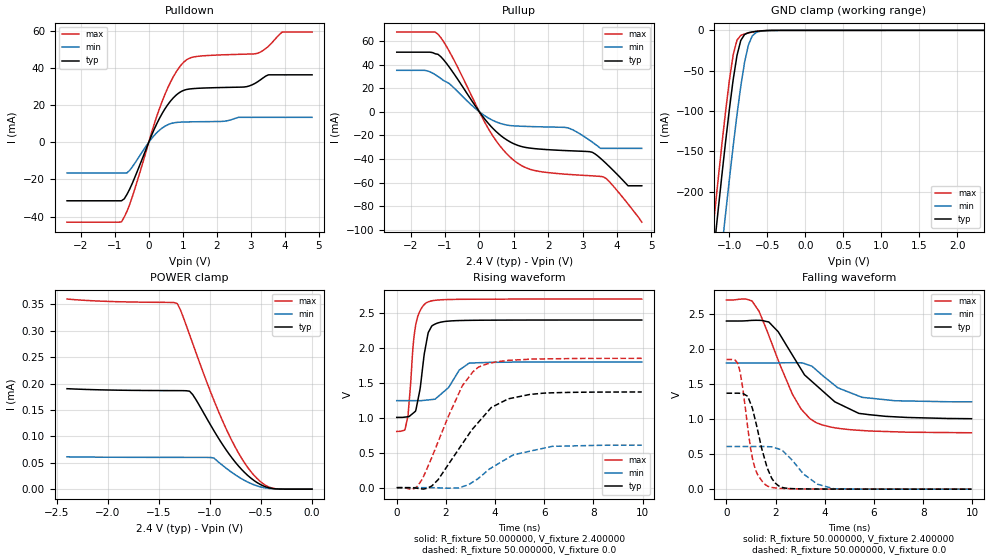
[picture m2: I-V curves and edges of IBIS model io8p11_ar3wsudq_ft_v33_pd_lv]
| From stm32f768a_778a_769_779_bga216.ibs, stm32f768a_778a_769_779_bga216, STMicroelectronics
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|   Model io8p11_ar3wsudq_ft_v33_pd_lv
[Model]  io8p11_ar3wsudq_ft_v33_pd_lv
Model_type I/O
Polarity   Non-Inverting
Enable   Active-Low
Vinl =   0.720000V
Vinh =   1.680000V
Vmeas =  1.200000V
Cref =   30.000000pF
Rref =   100.000000M
Vref =   0.0V
C_comp   3.742400pF   3.690400pF   3.817400pF
[Temperature Range]   25.000000   0.125000k   -40.000000
[Pullup Reference]   2.400000V   1.800000V   2.700000V
[Pulldown Reference]   0.0V   0.0V   0.0V
[POWER Clamp Reference]   2.400000V   1.800000V   2.700000V
[GND Clamp Reference]   0.0V   0.0V   0.0V
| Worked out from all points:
|   slope of the pulldown table from 0 to 0.36 V, typ, clamps not added: 25 ohm
|   slope of the pullup table from 0 to 0.36 V, typ, clamps not added: 27.7 ohm
|   GND clamp passes 1 mA (typ) near -0.62 V on its own axis
|   rising waveform, R_fixture 50.000000, V_fixture 2.400000: 20-80 % time 350ps typ, 712ps min, 273ps max; typ from 1 V to 2.4 V
|   rising waveform, R_fixture 50.000000, V_fixture 0.0: 20-80 % time 1.73ns typ, 1.68ns min, 1.37ns max; typ from 0 V to 1.37 V
|   falling waveform, R_fixture 50.000000, V_fixture 2.400000: 20-80 % time 1.96ns typ, 1.49ns min, 1.39ns max; typ from 2.4 V to 1 V
|   falling waveform, R_fixture 50.000000, V_fixture 0.0: 20-80 % time 598ps typ, 1.04ns min, 459ps max; typ from 1.37 V to 0 V
[Pulldown]
|Voltage   I(typ)   I(min)   I(max)
-2.4V     -31.47mA   -16.45mA   -43.01mA
-800mV    -31.47mA   -16.45mA   -42.85mA
-480mV    -21.98mA   -13.17mA   -29.2mA
80mV      3.63mA     1.966mA    5.014mA
480mV     18.15mA    8.738mA    26.02mA
800mV     25.38mA    10.72mA    37.77mA
1.12V     28.53mA    11.02mA    44.6mA
2.8V      29.84mA    13.49mA    47.53mA
3.2V      32.65mA    13.49mA    48.04mA
3.52V     36.4mA     13.49mA    51.82mA
3.92V     36.4mA     13.49mA    59.44mA
4.8V      36.4mA     13.49mA    59.44mA
[Pullup]
|Voltage   I(typ)   I(min)   I(max)
-2.4V     50.45mA    35.08mA    67.45mA
-1.52V    50.45mA    34.74mA    67.45mA
-1.2V     48.61mA    29.87mA    65.6mA
-800mV    34.81mA    21.95mA    47.28mA
320mV     -11.75mA   -6.207mA   -17.08mA
1.04V     -27.53mA   -11.97mA   -41.91mA
1.6V      -31.13mA   -12.58mA   -49.63mA
2.56V     -32.88mA   -13.52mA   -52.9mA
3.28V     -34.25mA   -25.62mA   -54.18mA
3.6V      -41.44mA   -30.95mA   -55.03mA
4.32V     -62.61mA   -30.95mA   -77.98mA
4.72V     -62.61mA   -30.95mA   -93.4mA
[GND_clamp]
|Voltage   I(typ)   I(min)   I(max)
-2.4V     -1.437A    -1.518A    -1.41A
-1.25V    -315.9mA   -407.2mA   -278.2mA
-1.2V     -270.1mA   -361.3mA   -232.1mA
-1.15V    -225mA     -316mA     -186.8mA
-1.1V     -180.9mA   -271.3mA   -142.7mA
-1.05V    -138.2mA   -227.5mA   -100.5mA
-950mV    -61.14mA   -143.6mA   -30.44mA
-900mV    -31.24mA   -104.7mA   -12.15mA
-850mV    -12.5mA    -69.41mA   -6.236mA
-750mV    -2.91mA    -18.35mA   -3.195mA
-600mV    -761.5uA   -1.227mA   -751.9uA
2.35V     58.09uA    37.93uA    67.25uA
[POWER_clamp]
|Voltage   I(typ)   I(min)   I(max)
-2.4V     190.2uA    61.19uA    359.9uA
-1.32V    186.6uA    60.14uA    351.2uA
-1.29V    186.5uA    60.13uA    339.6uA
-1.2V     185.4uA    60.11uA    292.6uA
-1.17V    179.2uA    60.11uA    276.3uA
-960mV    110.2uA    58.62uA    167.5uA
-870mV    82.44uA    43.99uA    126.3uA
-750mV    50.58uA    26.92uA    78.64uA
-630mV    25.94uA    13.41uA    41.02uA
-510mV    9.22uA     4.527uA    14.97uA
-420mV    2.425uA    1.38uA     3.75uA
0V        0A         0A         0A
[Ramp]
| variable   typ   min   max
dV/dt_r  0.82104/1.72804n   0.36944/1.76414n   1.11072/1.36584n
dV/dt_f  0.83202/1.95959n   0.33240/1.49371n   1.13554/1.39031n
R_load = 50.000000
[Rising Waveform]
R_fixture= 50.000000
V_fixture= 2.400000
V_fixture_min= 1.800000
V_fixture_max= 2.700000
|time   V(typ)   V(min)   V(max)
0s        1.005V     1.245V     804.5mV
320.3ps   1.009V     1.245V     824.1mV
460.5ps   1.015V     1.245V     1.036V
660.7ps   1.064V     1.245V     2.009V
760.8ps   1.093V     1.245V     2.306V
961ps     1.439V     1.245V     2.539V
1.221ns   2.108V     1.253V     2.649V
1.562ns   2.341V     1.266V     2.681V
2.943ns   2.394V     1.781V     2.696V
9.97ns    2.399V     1.799V     2.699V
[Rising Waveform]
R_fixture= 50.000000
V_fixture= 0.0
V_fixture_min= 0.0
V_fixture_max= 0.0
|time   V(typ)   V(min)   V(max)
0s        78.29uV    35.48uV    223.5uV
860.9ps   -10.31mV   60.75uV    27.05mV
1.261ns   -5.229mV   -407.6uV   297.9mV
1.682ns   113.2mV    -2.537mV   655mV
2.663ns   624.6mV    12.36mV    1.454V
3.323ns   935.6mV    133.7mV    1.724V
3.864ns   1.151V     286.5mV    1.787V
5.405ns   1.333V     520.7mV    1.838V
6.326ns   1.357V     591.3mV    1.844V
9.97ns    1.369V     608.5mV    1.85V
[Falling Waveform]
R_fixture= 50.000000
V_fixture= 2.400000
V_fixture_min= 1.800000
V_fixture_max= 2.700000
|time   V(typ)   V(min)   V(max)
0s        2.399V     1.799V     2.699V
1.041ns   2.408V     1.799V     2.684V
1.321ns   2.409V     1.799V     2.54V
1.722ns   2.385V     1.799V     2.194V
2.683ns   1.913V     1.804V     1.355V
3.043ns   1.707V     1.802V     1.141V
3.664ns   1.478V     1.698V     946.3mV
4.525ns   1.227V     1.447V     869.2mV
5.385ns   1.081V     1.328V     840.1mV
9.97ns    1.005V     1.245V     804.5mV
[Falling Waveform]
R_fixture= 50.000000
V_fixture= 0.0
V_fixture_min= 0.0
V_fixture_max= 0.0
|time   V(typ)   V(min)   V(max)
0s        1.369V     608.5mV    1.85V
460.5ps   1.37V      608.4mV    1.794V
660.7ps   1.365V     608.3mV    1.445V
860.9ps   1.326V     608.2mV    893.6mV
1.181ns   973mV      608.1mV    276.5mV
1.662ns   300.2mV    606.4mV    45.36mV
2.262ns   25.69mV    557.4mV    9.738mV
3.143ns   3.643mV    213.8mV    3.238mV
4.364ns   1.366mV    6.242mV    1.176mV
9.97ns    78.29uV    35.48uV    223.5uV
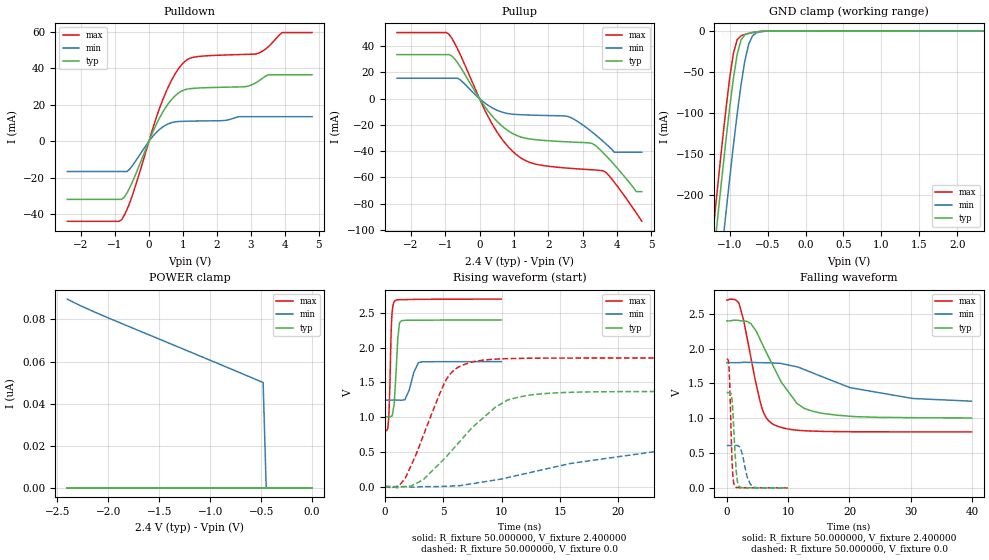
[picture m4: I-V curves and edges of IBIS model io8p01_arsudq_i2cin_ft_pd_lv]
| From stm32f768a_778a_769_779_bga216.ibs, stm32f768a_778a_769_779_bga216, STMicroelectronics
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|   Model io8p01_arsudq_i2cin_ft_pd_lv
[Model]  io8p01_arsudq_i2cin_ft_pd_lv
Model_type I/O
Polarity   Non-Inverting
Enable   Active-Low
Vinl =   0.720000V
Vinh =   1.680000V
Vmeas =  1.200000V
Cref =   50.000000pF
Rref =   100.000000M
Vref =   0.0V
C_comp   2.230300pF   2.174000pF   2.332300pF
[Temperature Range]   25.000000   0.125000k   -40.000000
[Pullup Reference]   2.400000V   1.800000V   2.700000V
[Pulldown Reference]   0.0V   0.0V   0.0V
[POWER Clamp Reference]   2.400000V   1.800000V   2.700000V
[GND Clamp Reference]   0.0V   0.0V   0.0V
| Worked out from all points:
|   slope of the pulldown table from 0 to 0.36 V, typ, clamps not added: 25 ohm
|   slope of the pullup table from 0 to 0.36 V, typ, clamps not added: 27.7 ohm
|   GND clamp passes 1 mA (typ) near -0.62 V on its own axis
|   rising waveform, R_fixture 50.000000, V_fixture 2.400000: 20-80 % time 273ps typ, 605ps min, 184ps max; typ from 1 V to 2.4 V
|   rising waveform, R_fixture 50.000000, V_fixture 0.0: 20-80 % time 4.8ns typ, 12.1ns min, 2.64ns max; typ from 0 V to 1.37 V
|   falling waveform, R_fixture 50.000000, V_fixture 2.400000: 20-80 % time 5.34ns typ, 12.6ns min, 2.67ns max; typ from 2.4 V to 1 V
|   falling waveform, R_fixture 50.000000, V_fixture 0.0: 20-80 % time 524ps typ, 972ps min, 384ps max; typ from 1.37 V to 0 V
[Pulldown]
|Voltage   I(typ)   I(min)   I(max)
-2.4V     -31.73mA   -16.51mA   -43.74mA
-800mV    -31.73mA   -16.51mA   -42.87mA
-480mV    -21.98mA   -13.17mA   -29.2mA
80mV      3.63mA     1.966mA    5.014mA
480mV     18.15mA    8.738mA    26.02mA
800mV     25.38mA    10.72mA    37.77mA
1.12V     28.53mA    11.02mA    44.6mA
2.8V      29.84mA    13.49mA    47.53mA
3.2V      32.65mA    13.49mA    48.04mA
3.52V     36.42mA    13.49mA    51.83mA
3.92V     36.42mA    13.49mA    59.49mA
4.8V      36.42mA    13.49mA    59.49mA
[Pullup]
|Voltage   I(typ)   I(min)   I(max)
-2.4V     33.57mA    15.56mA    50.37mA
-960mV    33.57mA    15.56mA    50.37mA
-560mV    24.29mA    14.3mA     33.54mA
320mV     -11.75mA   -6.207mA   -17.08mA
960mV     -26.47mA   -11.82mA   -40.02mA
1.52V     -30.88mA   -12.51mA   -49.05mA
2.56V     -32.88mA   -13.48mA   -52.9mA
3.28V     -34.19mA   -25.52mA   -54.18mA
3.6V      -41.31mA   -32.62mA   -54.97mA
3.92V     -50.32mA   -40.8mA    -63.63mA
4.56V     -70.8mA    -40.8mA    -87.08mA
4.72V     -70.8mA    -40.8mA    -93.4mA
[GND_clamp]
|Voltage   I(typ)   I(min)   I(max)
-2.4V     -1.424A    -1.508A    -1.393A
-1.25V    -311.2mA   -401.9mA   -273.3mA
-1.2V     -265.4mA   -356.1mA   -227.2mA
-1.15V    -220.4mA   -310.8mA   -181.9mA
-1.1V     -176.3mA   -266.2mA   -137.9mA
-1.05V    -133.8mA   -222.5mA   -95.87mA
-950mV    -57.3mA    -138.9mA   -26.99mA
-900mV    -28.28mA   -100.4mA   -10.6mA
-850mV    -11.02mA   -65.54mA   -5.972mA
-750mV    -2.846mA   -16.51mA   -3.192mA
-600mV    -761.3uA   -1.173mA   -751.9uA
2.35V     58.09uA    37.92uA    67.25uA
[POWER_clamp]
|Voltage   I(typ)   I(min)   I(max)
-2.4V     0A         89.62nA    0A
-2.04V    0A         81.57nA    0A
-480mV    0A         50.01nA    0A
-450mV    0A         0A         0A
0V        0A         0A         0A
[Ramp]
| variable   typ   min   max
dV/dt_r  0.82158/4.79824n   0.38411/12.99045n   1.11042/2.64258n
dV/dt_f  0.83670/5.34237n   0.32364/13.42571n   1.13744/2.67157n
R_load = 50.000000
[Rising Waveform]
R_fixture= 50.000000
V_fixture= 2.400000
V_fixture_min= 1.800000
V_fixture_max= 2.700000
|time   V(typ)   V(min)   V(max)
0s        1.005V     1.245V     804.2mV
240.2ps   1.005V     1.245V     824.9mV
340.3ps   1.005V     1.245V     987.2mV
600.6ps   1.014V     1.246V     2.44V
860.9ps   1.346V     1.246V     2.674V
1.121ns   2.146V     1.245V     2.689V
1.381ns   2.381V     1.244V     2.691V
1.722ns   2.394V     1.251V     2.692V
2.903ns   2.395V     1.785V     2.696V
9.97ns    2.399V     1.799V     2.699V
[Rising Waveform]
R_fixture= 50.000000
V_fixture= 0.0
V_fixture_min= 0.0
V_fixture_max= 0.0
|time   V(typ)   V(min)   V(max)
0s        178.1uV    73.91uV    433.7uV
1.201ns   -14.27mV   132.9uV    8.83mV
1.762ns   -1.061mV   -612.3uV   121.8mV
3.283ns   97.59mV    -600uV     725.8mV
5.125ns   404mV      3.401mV    1.498V
7.287ns   813.5mV    36mV       1.785V
10.49ns   1.244V     127.8mV    1.842V
13.13ns   1.33V      227.8mV    1.849V
24.82ns   1.369V     542.8mV    1.851V
39.88ns   1.369V     608.4mV    1.851V
[Falling Waveform]
R_fixture= 50.000000
V_fixture= 2.400000
V_fixture_min= 1.800000
V_fixture_max= 2.700000
|time   V(typ)   V(min)   V(max)
0s        2.399V     1.799V     2.699V
2.002ns   2.404V     1.8V       2.652V
2.803ns   2.397V     1.804V     2.387V
3.924ns   2.361V     1.803V     1.878V
5.766ns   2.072V     1.798V     1.136V
7.688ns   1.729V     1.794V     907.8mV
11.45ns   1.211V     1.739V     828.9mV
14.01ns   1.101V     1.651V     815.7mV
20.1ns    1.029V     1.44V      806.6mV
39.88ns   1.005V     1.245V     804.2mV
[Falling Waveform]
R_fixture= 50.000000
V_fixture= 0.0
V_fixture_min= 0.0
V_fixture_max= 0.0
|time   V(typ)   V(min)   V(max)
0s        1.369V     608.4mV    1.851V
380.4ps   1.369V     608.4mV    1.717V
480.5ps   1.369V     608.4mV    1.52V
880.9ps   1.253V     608.2mV    364.6mV
1.041ns   1.033V     607.9mV    129.9mV
1.261ns   648.8mV    607.8mV    34.04mV
1.702ns   115.4mV    609.8mV    4.511mV
2.062ns   17.39mV    592.2mV    2.525mV
3.864ns   1.054mV    51mV       1.255mV
9.97ns    178.1uV    73.91uV    433.7uV
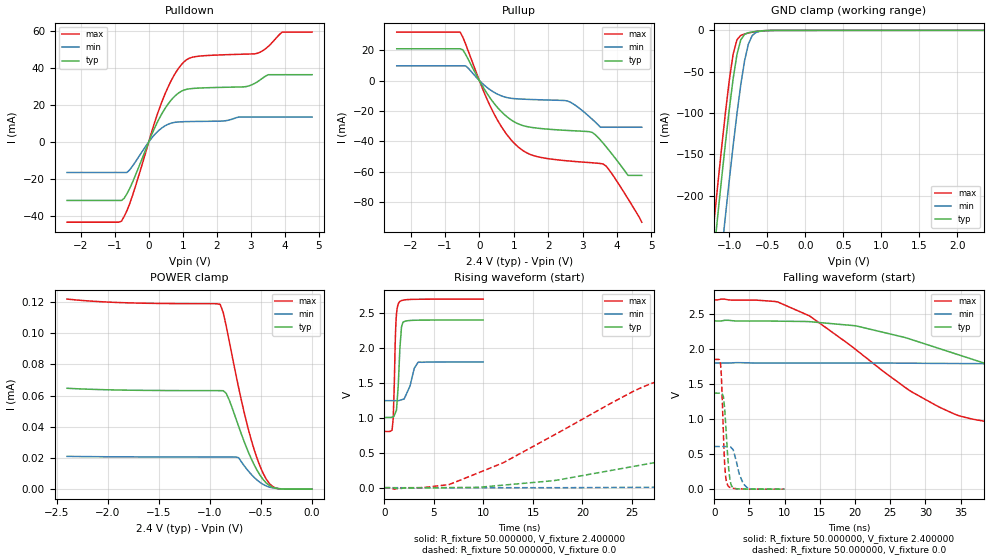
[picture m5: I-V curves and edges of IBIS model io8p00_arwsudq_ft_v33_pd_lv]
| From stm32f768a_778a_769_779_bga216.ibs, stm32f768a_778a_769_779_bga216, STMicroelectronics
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|   Model io8p00_arwsudq_ft_v33_pd_lv
[Model]  io8p00_arwsudq_ft_v33_pd_lv
Model_type I/O
Polarity   Non-Inverting
Enable   Active-Low
Vinl =   0.720000V
Vinh =   1.680000V
Vmeas =  1.200000V
Cref =   50.000000pF
Rref =   100.000000M
Vref =   0.0V
C_comp   2.828400pF   2.771400pF   2.910300pF
[Temperature Range]   25.000000   0.125000k   -40.000000
[Pullup Reference]   2.400000V   1.800000V   2.700000V
[Pulldown Reference]   0.0V   0.0V   0.0V
[POWER Clamp Reference]   2.400000V   1.800000V   2.700000V
[GND Clamp Reference]   0.0V   0.0V   0.0V
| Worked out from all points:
|   slope of the pulldown table from 0 to 0.36 V, typ, clamps not added: 25 ohm
|   slope of the pullup table from 0 to 0.36 V, typ, clamps not added: 27.7 ohm
|   GND clamp passes 1 mA (typ) near -0.62 V on its own axis
|   rising waveform, R_fixture 50.000000, V_fixture 2.400000: 20-80 % time 322ps typ, 710ps min, 219ps max; typ from 1 V to 2.4 V
|   rising waveform, R_fixture 50.000000, V_fixture 0.0: 20-80 % time 30.9ns typ, 81.7ns min, 14.6ns max; typ from 0 V to 1.37 V
|   falling waveform, R_fixture 50.000000, V_fixture 2.400000: 20-80 % time 28.7ns typ, 81.5ns min, 16.1ns max; typ from 2.4 V to 1 V
|   falling waveform, R_fixture 50.000000, V_fixture 0.0: 20-80 % time 551ps typ, 1.05ns min, 407ps max; typ from 1.37 V to 0 V
[Pulldown]
|Voltage   I(typ)   I(min)   I(max)
-2.4V     -31.66mA   -16.51mA   -43.43mA
-800mV    -31.66mA   -16.51mA   -42.86mA
-480mV    -21.98mA   -13.17mA   -29.2mA
80mV      3.63mA     1.966mA    5.014mA
480mV     18.15mA    8.738mA    26.02mA
800mV     25.38mA    10.72mA    37.77mA
1.12V     28.53mA    11.02mA    44.6mA
2.8V      29.84mA    13.48mA    47.53mA
3.2V      32.65mA    13.48mA    48.04mA
3.52V     36.42mA    13.48mA    51.83mA
3.92V     36.42mA    13.48mA    59.48mA
4.8V      36.42mA    13.48mA    59.48mA
[Pullup]
|Voltage   I(typ)   I(min)   I(max)
-2.4V     20.89mA    9.66mA     31.89mA
-560mV    20.89mA    9.66mA     31.89mA
-400mV    17.28mA    9.66mA     24.06mA
320mV     -11.75mA   -6.207mA   -17.08mA
640mV     -20.52mA   -10.1mA    -30.35mA
960mV     -26.47mA   -11.82mA   -40.02mA
1.52V     -30.88mA   -12.51mA   -49.05mA
2.56V     -32.88mA   -13.49mA   -52.9mA
3.28V     -34.2mA    -25.51mA   -54.18mA
3.6V      -41.34mA   -30.77mA   -55mA
4.32V     -62.5mA    -30.77mA   -77.89mA
4.72V     -62.5mA    -30.77mA   -93.3mA
[GND_clamp]
|Voltage   I(typ)   I(min)   I(max)
-2.4V     -1.428A    -1.51A     -1.401A
-1.2V     -266.4mA   -356.3mA   -229.4mA
-1.15V    -221.3mA   -311mA     -184.1mA
-1.1V     -177.3mA   -266.4mA   -140mA
-1.05V    -134.8mA   -222.7mA   -97.98mA
-950mV    -58.22mA   -139.2mA   -28.55mA
-900mV    -29.04mA   -100.6mA   -11.28mA
-850mV    -11.42mA   -65.77mA   -6.081mA
-750mV    -2.864mA   -16.63mA   -3.193mA
-700mV    -1.925mA   -6.327mA   -2.195mA
-600mV    -761.3uA   -1.176mA   -751.9uA
2.35V     58.09uA    37.92uA    67.25uA
[POWER_clamp]
|Voltage   I(typ)   I(min)   I(max)
-2.4V     64.71uA    21.03uA    121.9uA
-1.86V    63.55uA    20.74uA    119.6uA
-900mV    63.18uA    20.63uA    118.5uA
-870mV    63.14uA    20.63uA    113.2uA
-840mV    61.36uA    20.62uA    104.3uA
-720mV    40.37uA    20.18uA    65.28uA
-630mV    24.69uA    12.08uA    39.85uA
-540mV    12.26uA    5.907uA    20uA
-480mV    6.236uA    3.061uA    10.23uA
-420mV    2.4uA      1.365uA    3.726uA
-360mV    667.9nA    564nA      839.6nA
0V        0A         0A         0A
[Ramp]
| variable   typ   min   max
dV/dt_r  0.82158/30.91104n   0.36271/83.77680n   1.11054/14.60240n
dV/dt_f  0.83664/28.69719n   0.32706/81.70446n   1.13680/16.06318n
R_load = 50.000000
[Rising Waveform]
R_fixture= 50.000000
V_fixture= 2.400000
V_fixture_min= 1.800000
V_fixture_max= 2.700000
|time   V(typ)   V(min)   V(max)
0s        1.005V     1.245V     804.1mV
780.8ps   1.011V     1.245V     844mV
880.9ps   1.015V     1.245V     986.6mV
1.161ns   1.091V     1.245V     2.379V
1.381ns   1.445V     1.245V     2.624V
1.481ns   1.756V     1.248V     2.654V
1.722ns   2.301V     1.258V     2.676V
1.882ns   2.369V     1.265V     2.683V
3.403ns   2.397V     1.796V     2.696V
9.97ns    2.399V     1.799V     2.699V
[Rising Waveform]
R_fixture= 50.000000
V_fixture= 0.0
V_fixture_min= 0.0
V_fixture_max= 0.0
|time   V(typ)   V(min)   V(max)
0s        8.172nV    277.6nV    27.6nV
7.007ns   1.534mV    -64.06uV   71.3mV
17.02ns   99.48mV    85.71uV    745.3mV
28.53ns   390.5mV    6.94mV     1.565V
35.54ns   586.7mV    17.4mV     1.729V
44.04ns   832.1mV    46.3mV     1.798V
61.06ns   1.19V      104.1mV    1.84V
85.09ns   1.329V     220.6mV    1.848V
153.2ns   1.367V     509.8mV    1.851V
249.2ns   1.369V     608.5mV    1.851V
[Falling Waveform]
R_fixture= 50.000000
V_fixture= 2.400000
V_fixture_min= 1.800000
V_fixture_max= 2.700000
|time   V(typ)   V(min)   V(max)
0s        2.399V     1.799V     2.699V
9.009ns   2.396V     1.798V     2.67V
13.51ns   2.389V     1.798V     2.472V
20.02ns   2.33V      1.798V     1.997V
32.03ns   2.003V     1.793V     1.167V
45.05ns   1.577V     1.77V      901.7mV
62.06ns   1.217V     1.707V     843.8mV
85.09ns   1.077V     1.579V     818.2mV
157.2ns   1.012V     1.324V     804.9mV
249.2ns   1.005V     1.245V     804.1mV
[Falling Waveform]
R_fixture= 50.000000
V_fixture= 0.0
V_fixture_min= 0.0
V_fixture_max= 0.0
|time   V(typ)   V(min)   V(max)
0s        1.369V     608.5mV    1.851V
900.9ps   1.37V      608.3mV    1.791V
1.081ns   1.366V     608.2mV    1.462V
1.481ns   1.154V     607.9mV    367.9mV
1.922ns   469.3mV    609.1mV    55.96mV
2.262ns   119.6mV    606.1mV    24.15mV
2.723ns   18.74mV    551.1mV    11.47mV
3.584ns   3.171mV    208.2mV    4.054mV
4.805ns   948uV      9.338mV    1.209mV
9.97ns    8.172nV    277.6nV    27.6nV
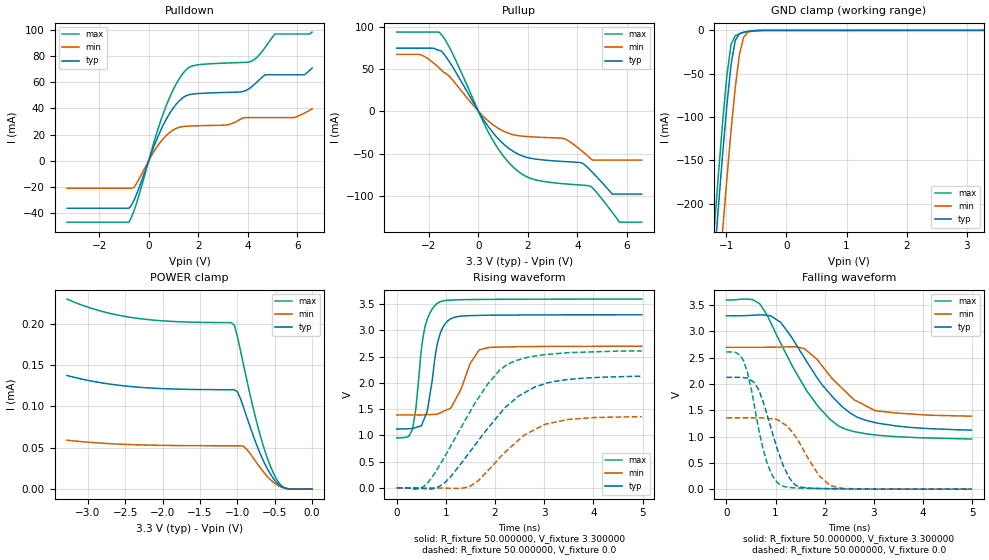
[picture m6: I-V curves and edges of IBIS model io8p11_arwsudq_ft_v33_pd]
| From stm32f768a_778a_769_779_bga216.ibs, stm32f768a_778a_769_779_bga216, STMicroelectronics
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|   Model io8p11_arwsudq_ft_v33_pd
[Model]  io8p11_arwsudq_ft_v33_pd
Model_type I/O
Polarity   Non-Inverting
Enable   Active-Low
Vinl =   0.990000V
Vinh =   2.310000V
Vmeas =  1.650000V
Cref =   30.000000pF
Rref =   100.000000M
Vref =   0.0V
C_comp   2.911600pF   2.826600pF   2.984500pF
[Temperature Range]   25.000000   0.125000k   -40.000000
[Pullup Reference]   3.300000V   2.700000V   3.600000V
[Pulldown Reference]   0.0V   0.0V   0.0V
[POWER Clamp Reference]   3.300000V   2.700000V   3.600000V
[GND Clamp Reference]   0.0V   0.0V   0.0V
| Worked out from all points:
|   slope of the pulldown table from 0 to 0.495 V, typ, clamps not added: 20.9 ohm
|   slope of the pullup table from 0 to 0.495 V, typ, clamps not added: 22.6 ohm
|   GND clamp passes 1 mA (typ) near -0.62 V on its own axis
|   rising waveform, R_fixture 50.000000, V_fixture 3.300000: 20-80 % time 222ps typ, 364ps min, 191ps max; typ from 1.12 V to 3.3 V
|   rising waveform, R_fixture 50.000000, V_fixture 0.0: 20-80 % time 1.14ns typ, 961ps min, 1.02ns max; typ from 0 V to 2.13 V
|   falling waveform, R_fixture 50.000000, V_fixture 3.300000: 20-80 % time 1.02ns typ, 830ps min, 1ns max; typ from 3.3 V to 1.12 V
|   falling waveform, R_fixture 50.000000, V_fixture 0.0: 20-80 % time 437ps typ, 538ps min, 360ps max; typ from 2.13 V to 0 V
[Pulldown]
|Voltage   I(typ)   I(min)   I(max)
-3.3V     -36.38mA   -21.07mA   -47.08mA
-800mV    -36.38mA   -21.07mA   -47.08mA
-600mV    -30.5mA    -20.54mA   -38.69mA
700mV     31.4mA     19.11mA    41.71mA
1.2V      45.15mA    25.37mA    61.75mA
1.6V      50.35mA    26.5mA     71.06mA
3.1V      52.27mA    27.26mA    74.75mA
4.1V      55.7mA     33.02mA    75.8mA
4.7V      65.79mA    33.02mA    86.63mA
5.1V      65.79mA    33.02mA    97.02mA
6.3V      65.87mA    36.5mA     97.02mA
6.6V      70.92mA    39.71mA    98.48mA
[Pullup]
|Voltage   I(typ)   I(min)   I(max)
-3.3V     74.74mA    67.41mA    93.78mA
-2.3V     74.74mA    66.57mA    93.78mA
-1.5V     71.46mA    49mA       91.15mA
500mV     -22.07mA   -14mA      -30.03mA
1.6V      -50.64mA   -28.81mA   -70.96mA
2.3V      -56.49mA   -30.49mA   -81.16mA
3.5V      -59.53mA   -32.66mA   -85.92mA
4.2V      -61.45mA   -47.47mA   -87.46mA
4.5V      -69.1mA    -55.02mA   -88.4mA
5.4V      -98mA      -57.7mA    -119.3mA
5.7V      -98mA      -57.7mA    -131.3mA
6.6V      -98mA      -57.7mA    -131.3mA
[GND_clamp]
|Voltage   I(typ)   I(min)   I(max)
-3.3V     -2.32A     -2.397A    -2.296A
-1.2V     -266.4mA   -356.3mA   -229.4mA
-1.13V    -203.6mA   -293.1mA   -166.3mA
-1.06V    -143.2mA   -231.4mA   -106.2mA
-990mV    -86.95mA   -171.8mA   -52.65mA
-920mV    -39.66mA   -115.8mA   -16.37mA
-850mV    -11.5mA    -65.84mA   -6.125mA
-780mV    -3.846mA   -27.59mA   -3.894mA
-710mV    -2.102mA   -7.761mA   -2.396mA
-640mV    -1.159mA   -2.138mA   -1.234mA
-570mV    -535.1uA   -809uA     -490.2uA
3.28V     81.28uA    57.87uA    93.98uA
[POWER_clamp]
|Voltage   I(typ)   I(min)   I(max)
-3.28V    137.3uA    59.14uA    229.6uA
-2.36V    123.4uA    53.65uA    206.6uA
-1.08V    120.1uA    52.41uA    201.1uA
-1.04V    120uA      52.41uA    198uA
-1V       117.7uA    52.4uA     184.5uA
-920mV    99.46uA    51.91uA    151.2uA
-720mV    48.42uA    29.12uA    73.51uA
-600mV    24.82uA    15.47uA    37.72uA
-520mV    13.1uA     8.45uA     19.84uA
-440mV    5.058uA    3.61uA     7.276uA
-360mV    1.193uA    1.129uA    1.311uA
0V        0A         0A         0A
[Ramp]
| variable   typ   min   max
dV/dt_r  1.26546/1.13882n   0.80862/0.95608n   1.56156/1.02292n
dV/dt_f  1.28214/1.01194n   0.77616/0.82055n   1.57188/1.00030n
R_load = 50.000000
[Rising Waveform]
R_fixture= 50.000000
V_fixture= 3.300000
V_fixture_min= 2.700000
V_fixture_max= 3.600000
|time   V(typ)   V(min)   V(max)
0s        1.123V     1.391V     953.8mV
320.3ps   1.132V     1.39V      1.116V
390.4ps   1.152V     1.39V      1.523V
500.5ps   1.184V     1.39V      2.633V
620.6ps   1.46V      1.395V     3.212V
850.9ps   2.834V     1.417V     3.532V
1.101ns   3.223V     1.522V     3.578V
1.491ns   3.282V     2.367V     3.589V
1.682ns   3.287V     2.63V      3.591V
4.985ns   3.299V     2.699V     3.598V
[Rising Waveform]
R_fixture= 50.000000
V_fixture= 0.0
V_fixture_min= 0.0
V_fixture_max= 0.0
|time   V(typ)   V(min)   V(max)
0s        214.8uV    83.29uV    610.9uV
550.6ps   -11.26mV   -120.3uV   29.4mV
951ps     78.66mV    -4.051mV   559.2mV
1.481ns   679.7mV    25.48mV    1.437V
1.852ns   1.134V     325.4mV    1.98V
2.232ns   1.553V     707.1mV    2.34V
2.593ns   1.811V     1.006V     2.472V
3.023ns   1.988V     1.215V     2.54V
3.493ns   2.066V     1.306V     2.577V
4.985ns   2.127V     1.358V     2.61V
[Falling Waveform]
R_fixture= 50.000000
V_fixture= 3.300000
V_fixture_min= 2.700000
V_fixture_max= 3.600000
|time   V(typ)   V(min)   V(max)
0s        3.299V     2.699V     3.598V
530.5ps   3.309V     2.699V     3.607V
670.7ps   3.314V     2.699V     3.531V
1.101ns   3.175V     2.704V     2.78V
1.582ns   2.505V     2.676V     1.954V
1.862ns   2.093V     2.445V     1.577V
2.292ns   1.628V     1.975V     1.196V
2.663ns   1.368V     1.67V      1.083V
3.033ns   1.265V     1.491V     1.031V
4.985ns   1.123V     1.391V     953.8mV
[Falling Waveform]
R_fixture= 50.000000
V_fixture= 0.0
V_fixture_min= 0.0
V_fixture_max= 0.0
|time   V(typ)   V(min)   V(max)
0s        2.127V     1.358V     2.61V
350.4ps   2.122V     1.357V     2.439V
560.6ps   2.029V     1.357V     1.623V
670.7ps   1.861V     1.356V     1.073V
830.8ps   1.403V     1.348V     487.9mV
1.101ns   589.4mV    1.283V     79.49mV
1.401ns   80.19mV    1.006V     25.35mV
1.882ns   12.81mV    260mV      12.34mV
2.102ns   9.137mV    76.17mV    9.665mV
4.985ns   214.8uV    83.29uV    610.9uV
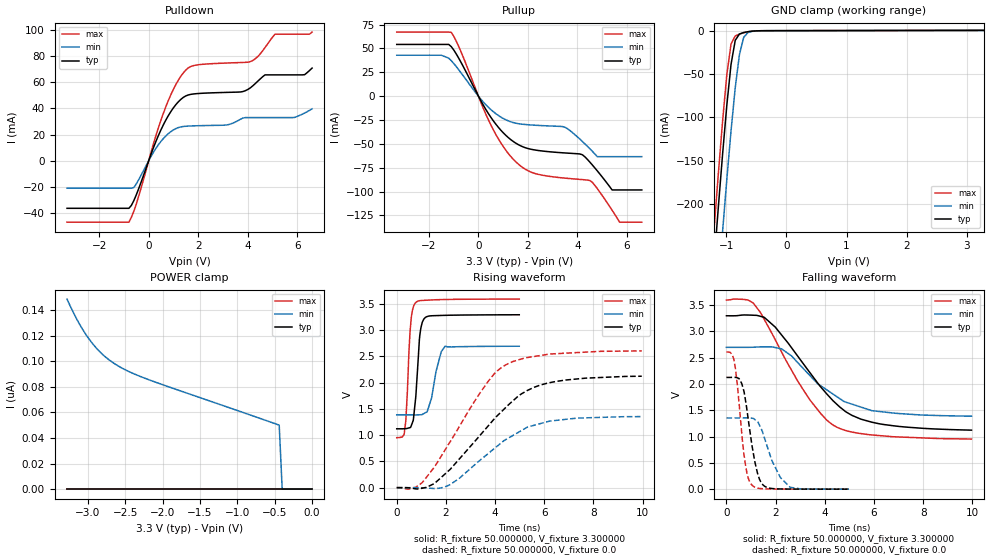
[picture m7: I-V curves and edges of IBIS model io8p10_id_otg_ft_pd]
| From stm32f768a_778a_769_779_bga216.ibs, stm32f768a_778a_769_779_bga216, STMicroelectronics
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|   Model io8p10_id_otg_ft_pd
[Model]  io8p10_id_otg_ft_pd
Model_type I/O
Polarity   Non-Inverting
Enable   Active-Low
Vinl =   0.990000V
Vinh =   2.310000V
Vmeas =  1.650000V
Cref =   40.000000pF
Rref =   100.000000M
Vref =   0.0V
C_comp   2.283100pF   2.214500pF   2.357400pF
[Temperature Range]   25.000000   0.125000k   -40.000000
[Pullup Reference]   3.300000V   2.700000V   3.600000V
[Pulldown Reference]   0.0V   0.0V   0.0V
[POWER Clamp Reference]   3.300000V   2.700000V   3.600000V
[GND Clamp Reference]   0.0V   0.0V   0.0V
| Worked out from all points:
|   slope of the pulldown table from 0 to 0.495 V, typ, clamps not added: 20.9 ohm
|   slope of the pullup table from 0 to 0.495 V, typ, clamps not added: 22.6 ohm
|   GND clamp passes 1 mA (typ) near -0.62 V on its own axis
|   rising waveform, R_fixture 50.000000, V_fixture 3.300000: 20-80 % time 194ps typ, 347ps min, 166ps max; typ from 1.12 V to 3.29 V
|   rising waveform, R_fixture 50.000000, V_fixture 0.0: 20-80 % time 2.52ns typ, 2.28ns min, 2.11ns max; typ from 0 V to 2.12 V
|   falling waveform, R_fixture 50.000000, V_fixture 3.300000: 20-80 % time 2.26ns typ, 2.05ns min, 2.03ns max; typ from 3.29 V to 1.12 V
|   falling waveform, R_fixture 50.000000, V_fixture 0.0: 20-80 % time 432ps typ, 669ps min, 337ps max; typ from 2.12 V to 0 V
[Pulldown]
|Voltage   I(typ)   I(min)   I(max)
-3.3V     -36.46mA   -21.1mA    -47.09mA
-800mV    -36.46mA   -21.1mA    -47.09mA
-600mV    -30.5mA    -20.54mA   -38.68mA
700mV     31.39mA    19.11mA    41.7mA
1.2V      45.14mA    25.37mA    61.74mA
1.6V      50.34mA    26.49mA    71.04mA
3.1V      52.26mA    27.25mA    74.74mA
4.1V      55.69mA    32.98mA    75.78mA
4.7V      65.7mA     32.98mA    86.67mA
5.1V      65.7mA     32.98mA    96.88mA
6.3V      65.85mA    36.49mA    96.88mA
6.6V      70.9mA     39.7mA     98.46mA
[Pullup]
|Voltage   I(typ)   I(min)   I(max)
-3.3V     54.22mA    42.9mA     67.16mA
-1.1V     51.99mA    37.29mA    66.89mA
500mV     -22.06mA   -14mA      -30.03mA
1.5V      -49.1mA    -28.3mA    -68.56mA
2.2V      -56.04mA   -30.32mA   -80.35mA
3.5V      -59.53mA   -32.65mA   -85.92mA
4.2V      -61.43mA   -47.48mA   -87.46mA
4.5V      -69.07mA   -55.13mA   -88.38mA
4.8V      -78.23mA   -63.4mA    -96.83mA
5.4V      -98.3mA    -63.4mA    -119.6mA
5.7V      -98.3mA    -63.4mA    -132.1mA
6.6V      -98.3mA    -63.4mA    -132.1mA
[GND_clamp]
|Voltage   I(typ)   I(min)   I(max)
-3.3V     -2.316A    -2.396A    -2.289A
-1.2V     -265.5mA   -356.1mA   -227.2mA
-1.13V    -202.7mA   -292.9mA   -164.2mA
-1.06V    -142.2mA   -231.2mA   -104.1mA
-990mV    -86mA      -171.6mA   -50.76mA
-920mV    -38.84mA   -115.5mA   -15.35mA
-850mV    -11.15mA   -65.63mA   -6.09mA
-780mV    -3.853mA   -27.45mA   -3.961mA
-710mV    -2.153mA   -7.739mA   -2.46mA
-640mV    -1.209mA   -2.169mA   -1.292mA
-570mV    -580.3uA   -846.3uA   -542.8uA
3.28V     342.5uA    239.2uA    398.5uA
[POWER_clamp]
|Voltage   I(typ)   I(min)   I(max)
-3.28V    0A         148.5nA    0A
-3.2V     0A         138.6nA    0A
-3.12V    0A         129.7nA    0A
-3.04V    0A         122nA      0A
-2.96V    0A         115.3nA    0A
-2.8V     0A         105.1nA    0A
-2.6V     0A         96.44nA    0A
-2.4V     0A         90.52nA    0A
-2.16V    0A         84.97nA    0A
-440mV    0A         50.04nA    0A
-400mV    0A         0A         0A
0V        0A         0A         0A
[Ramp]
| variable   typ   min   max
dV/dt_r  1.26426/2.51289n   0.80916/2.28463n   1.56204/2.11910n
dV/dt_f  1.28196/2.24730n   0.77772/2.03699n   1.57323/2.03479n
R_load = 50.000000
[Rising Waveform]
R_fixture= 50.000000
V_fixture= 3.300000
V_fixture_min= 2.700000
V_fixture_max= 3.600000
|time   V(typ)   V(min)   V(max)
0s        1.121V     1.387V     952.6mV
300.3ps   1.123V     1.387V     1.014V
370.4ps   1.125V     1.387V     1.277V
550.6ps   1.146V     1.387V     3.019V
670.7ps   1.28V      1.386V     3.436V
760.8ps   1.669V     1.386V     3.521V
940.9ps   2.912V     1.389V     3.563V
1.171ns   3.246V     1.429V     3.571V
1.972ns   3.284V     2.696V     3.585V
4.985ns   3.295V     2.695V     3.594V
[Rising Waveform]
R_fixture= 50.000000
V_fixture= 0.0
V_fixture_min= 0.0
V_fixture_max= 0.0
|time   V(typ)   V(min)   V(max)
0s        344.8uV    197.6uV    679.7uV
460.5ps   -2.481mV   133.5uV    -29mV
1.041ns   -10.08mV   -1.937mV   97.3mV
1.542ns   81.92mV    -17.45mV   398.2mV
2.162ns   343.7mV    55.55mV    866.7mV
3.744ns   1.189V     658.5mV    2.041V
4.444ns   1.532V     917.9mV    2.342V
5.305ns   1.85V      1.151V     2.479V
6.166ns   1.995V     1.262V     2.541V
9.97ns    2.124V     1.354V     2.607V
[Falling Waveform]
R_fixture= 50.000000
V_fixture= 3.300000
V_fixture_min= 2.700000
V_fixture_max= 3.600000
|time   V(typ)   V(min)   V(max)
0s        3.295V     2.695V     3.594V
880.9ps   3.309V     2.695V     3.594V
1.101ns   3.305V     2.697V     3.531V
1.542ns   3.263V     2.705V     3.223V
2.242ns   2.931V     2.665V     2.608V
3.383ns   2.222V     2.165V     1.704V
4.384ns   1.66V      1.792V     1.205V
5.105ns   1.402V     1.616V     1.085V
6.206ns   1.243V     1.477V     1.019V
9.97ns    1.121V     1.387V     952.6mV
[Falling Waveform]
R_fixture= 50.000000
V_fixture= 0.0
V_fixture_min= 0.0
V_fixture_max= 0.0
|time   V(typ)   V(min)   V(max)
0s        2.124V     1.354V     2.607V
300.3ps   2.125V     1.354V     2.468V
450.5ps   2.114V     1.354V     1.949V
620.6ps   2.01V      1.354V     1.071V
830.8ps   1.516V     1.356V     312.8mV
1.041ns   823.5mV    1.348V     76.36mV
1.451ns   99.48mV    1.109V     9.633mV
1.852ns   12.75mV    539.9mV    3.701mV
2.583ns   2.074mV    39.7mV     1.691mV
4.985ns   344.8uV    197.6uV    679.7uV
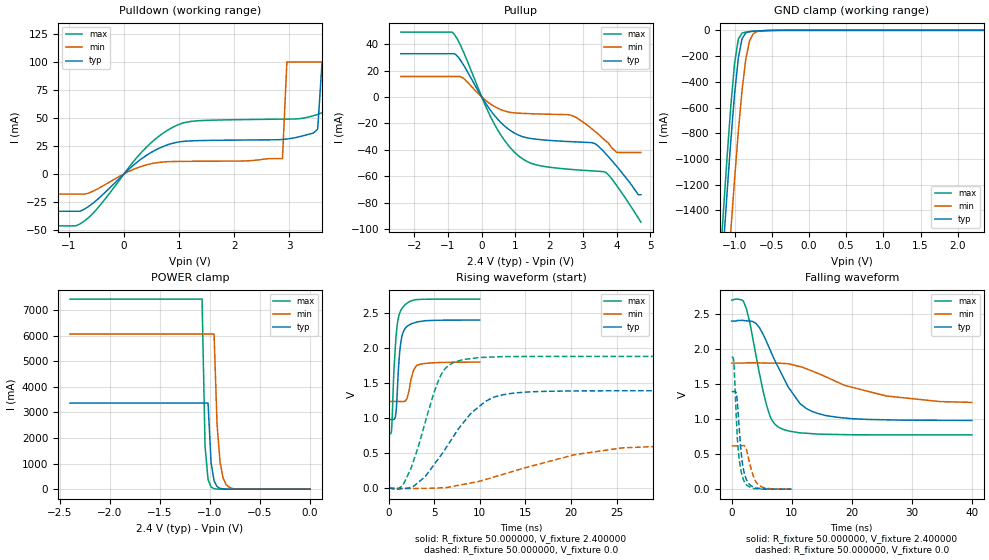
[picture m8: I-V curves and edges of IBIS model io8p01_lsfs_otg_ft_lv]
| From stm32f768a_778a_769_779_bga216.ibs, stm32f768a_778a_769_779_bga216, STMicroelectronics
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|   Model io8p01_lsfs_otg_ft_lv
[Model]  io8p01_lsfs_otg_ft_lv
Model_type I/O
Polarity   Non-Inverting
Enable   Active-Low
Vinl =   0.720000V
Vinh =   1.680000V
Vmeas =  1.200000V
Cref =   50.000000pF
Rref =   100.000000M
Vref =   0.0V
C_comp   7.971100pF   7.737700pF   8.264100pF
[Temperature Range]   25.000000   0.125000k   -40.000000
[Pullup Reference]   2.400000V   1.800000V   2.700000V
[Pulldown Reference]   0.0V   0.0V   0.0V
[POWER Clamp Reference]   2.400000V   1.800000V   2.700000V
[GND Clamp Reference]   0.0V   0.0V   0.0V
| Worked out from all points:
|   slope of the pulldown table from 0 to 0.36 V, typ, clamps not added: 24.1 ohm
|   slope of the pullup table from 0 to 0.36 V, typ, clamps not added: 26.8 ohm
|   GND clamp passes 1 mA (typ) near -0.52 V on its own axis
|   POWER clamp passes 1 mA (typ) near -0.81 V on its own axis
|   rising waveform, R_fixture 50.000000, V_fixture 2.400000: 20-80 % time 479ps typ, 592ps min, 491ps max; typ from 0.981 V to 2.4 V
|   rising waveform, R_fixture 50.000000, V_fixture 0.0: 20-80 % time 4.78ns typ, 10.6ns min, 2.68ns max; typ from 0 V to 1.39 V
|   falling waveform, R_fixture 50.000000, V_fixture 2.400000: 20-80 % time 5.25ns typ, 11.5ns min, 2.78ns max; typ from 2.4 V to 0.981 V
|   falling waveform, R_fixture 50.000000, V_fixture 0.0: 20-80 % time 915ps typ, 1.27ns min, 799ps max; typ from 1.39 V to 0 V
[Pulldown]
|Voltage   I(typ)   I(min)   I(max)
-2.4V     -33.44mA   -18.12mA   -46.52mA
-800mV    -33.44mA   -18.12mA   -44.78mA
1.04V     28.81mA    11.14mA    44.91mA
2.88V     30.71mA    13.65mA    48.89mA
2.96V     31.11mA    100mA      48.94mA
3.52V     40mA       100mA      53.15mA
3.6V      100mA      100mA      54.66mA
3.92V     100mA      100mA      60mA
4V        100mA      100mA      100mA
4.4V      100mA      100mA      100mA
4.48V     100mA      100mA      1A
4.8V      100mA      100mA      1A
[Pullup]
|Voltage   I(typ)   I(min)   I(max)
-2.4V     32.78mA    15.54mA    49.16mA
-880mV    32.78mA    15.54mA    49.16mA
-560mV    25.07mA    14.46mA    35.14mA
320mV     -12.14mA   -6.322mA   -17.91mA
960mV     -27.18mA   -12mA      -41.54mA
1.52V     -31.65mA   -12.71mA   -50.68mA
2.64V     -33.82mA   -13.73mA   -54.81mA
3.36V     -35.34mA   -26.1mA    -56.1mA
3.68V     -43.1mA    -33.3mA    -57.12mA
4V        -52.4mA    -42mA      -67mA
4.64V     -74mA      -42mA      -91.5mA
4.72V     -74mA      -42mA      -94.8mA
[GND_clamp]
|Voltage   I(typ)   I(min)   I(max)
-2.4V     -9.766A    -9.942A    -9.572A
-1.2V     -2.124A    -2.851A    -1.855A
-1.15V    -1.682A    -2.408A    -1.408A
-1.1V     -1.256A    -1.975A    -979.8mA
-1.05V    -854.9mA   -1.556A    -584.5mA
-1V       -496.5mA   -1.158A    -257.5mA
-950mV    -217.7mA   -789.6mA   -69.52mA
-900mV    -65.57mA   -469.8mA   -21.5mA
-850mV    -19.64mA   -226.4mA   -13.56mA
-800mV    -9.753mA   -84.21mA   -10.47mA
-700mV    -4.923mA   -9.884mA   -5.807mA
2.35V     0A         0A         0A
[POWER_clamp]
|Voltage   I(typ)   I(min)   I(max)
-2.4V     3.365A     6.064A     7.43A
-1.08V    3.365A     6.064A     7.43A
-1.05V    3.365A     6.064A     1.669A
-1.02V    3.365A     6.064A     375mA
-990mV    1.047A     6.064A     84.24mA
-960mV    325.6mA    6.064A     18.93mA
-930mV    101.3mA    2.529A     4.252mA
-900mV    31.51mA    1.055A     955.2uA
-870mV    9.804mA    440.1mA    214.6uA
-840mV    3.05mA     183.6mA    74.58uA
-720mV    28.58uA    5.557mA    74.58uA
0V        0A         0A         0A
[Ramp]
| variable   typ   min   max
dV/dt_r  0.83556/4.78028n   0.36986/10.63774n   1.12860/2.67630n
dV/dt_f  0.85117/5.24567n   0.32628/11.64314n   1.15501/2.78003n
R_load = 50.000000
[Rising Waveform]
R_fixture= 50.000000
V_fixture= 2.400000
V_fixture_min= 1.800000
V_fixture_max= 2.700000
|time   V(typ)   V(min)   V(max)
0s        981.5mV    1.239V     774.8mV
300.3ps   981.1mV    1.239V     837.2mV
520.5ps   982.4mV    1.239V     1.574V
720.7ps   1.022V     1.239V     2.039V
900.9ps   1.322V     1.239V     2.315V
1.161ns   1.903V     1.238V     2.489V
1.401ns   2.149V     1.237V     2.558V
2.002ns   2.31V      1.282V     2.641V
3.043ns   2.37V      1.752V     2.692V
9.97ns    2.4V       1.8V       2.7V
[Rising Waveform]
R_fixture= 50.000000
V_fixture= 0.0
V_fixture_min= 0.0
V_fixture_max= 0.0
|time   V(typ)   V(min)   V(max)
0s        15.25uV    8.522uV    105.5uV
1.602ns   -4.901mV   44.14uV    59.17mV
2.402ns   11.59mV    -6.807mV   274.5mV
3.924ns   159.3mV    -1.333mV   911.1mV
5.526ns   436.7mV    5.162mV    1.563V
7.207ns   763.6mV    31.75mV    1.8V
10.57ns   1.236V     123.4mV    1.869V
13.21ns   1.349V     225.7mV    1.879V
25.63ns   1.392V     576.2mV    1.881V
39.88ns   1.392V     617.9mV    1.881V
[Falling Waveform]
R_fixture= 50.000000
V_fixture= 2.400000
V_fixture_min= 1.800000
V_fixture_max= 2.700000
|time   V(typ)   V(min)   V(max)
0s        2.4V       1.8V       2.7V
2.402ns   2.404V     1.803V     2.585V
4.004ns   2.368V     1.805V     1.923V
5.766ns   2.11V      1.801V     1.21V
6.567ns   1.952V     1.8V       1.005V
8.008ns   1.693V     1.798V     874.2mV
11.37ns   1.22V      1.75V      804mV
14.57ns   1.074V     1.644V     785.2mV
25.71ns   990mV      1.331V     775.5mV
39.88ns   981.5mV    1.239V     774.8mV
[Falling Waveform]
R_fixture= 50.000000
V_fixture= 0.0
V_fixture_min= 0.0
V_fixture_max= 0.0
|time   V(typ)   V(min)   V(max)
0s        1.392V     617.9mV    1.881V
360.4ps   1.393V     617.9mV    1.803V
840.8ps   1.33V      617.8mV    889.7mV
1.281ns   831.6mV    617.4mV    405.7mV
1.622ns   480.6mV    619.1mV    232.9mV
2.002ns   263.4mV    621.8mV    124.4mV
2.743ns   89.32mV    459.9mV    43.02mV
3.704ns   27.09mV    161.3mV    8.717mV
4.484ns   12.51mV    57.87mV    3.203mV
9.97ns    15.25uV    8.522uV    105.5uV
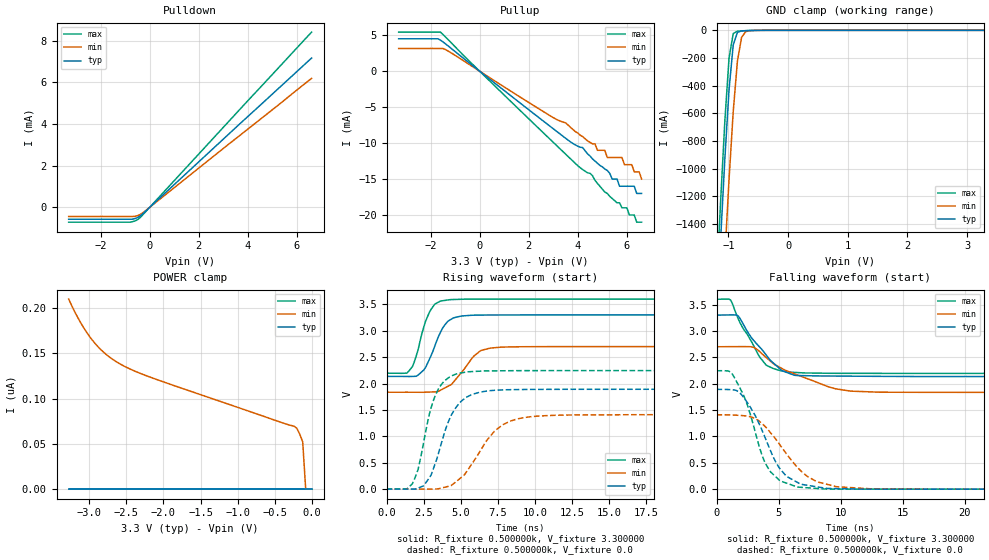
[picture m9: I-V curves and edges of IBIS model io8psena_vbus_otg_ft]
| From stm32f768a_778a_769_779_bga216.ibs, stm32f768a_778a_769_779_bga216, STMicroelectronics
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|   Model io8psena_vbus_otg_ft
[Model]  io8psena_vbus_otg_ft
Model_type 3-state
Polarity   Non-Inverting
Enable   Active-High
Vmeas =  1.650000V
Cref =   50.000000pF
Rref =   100.000000M
Vref =   0.0V
C_comp   3.300900pF   3.198000pF   3.426400pF
[Temperature Range]   25.000000   0.125000k   -40.000000
[Pullup Reference]   3.300000V   2.700000V   3.600000V
[Pulldown Reference]   0.0V   0.0V   0.0V
[POWER Clamp Reference]   3.300000V   2.700000V   3.600000V
[GND Clamp Reference]   0.0V   0.0V   0.0V
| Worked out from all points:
|   slope of the pulldown table from 0 to 0.495 V, typ, clamps not added: 915 ohm
|   slope of the pullup table from 0 to 0.495 V, typ, clamps not added: 371 ohm
|   GND clamp passes 1 mA (typ) near -0.61 V on its own axis
|   rising waveform, R_fixture 0.500000k, V_fixture 3.300000: 20-80 % time 1.08ns typ, 1.47ns min, 894ps max; typ from 2.13 V to 3.3 V
|   rising waveform, R_fixture 0.500000k, V_fixture 0.0: 20-80 % time 1.46ns typ, 2.13ns min, 1.14ns max; typ from 0 V to 1.89 V
|   falling waveform, R_fixture 0.500000k, V_fixture 3.300000: 20-80 % time 2.4ns typ, 4.43ns min, 1.98ns max; typ from 3.3 V to 2.13 V
|   falling waveform, R_fixture 0.500000k, V_fixture 0.0: 20-80 % time 2.31ns typ, 2.96ns min, 1.89ns max; typ from 1.89 V to 0 V
[Pulldown]
|Voltage   I(typ)   I(min)   I(max)
-3.3V     -568.8uA   -435.6uA   -711.6uA
-800mV    -568.8uA   -435.6uA   -711.6uA
-600mV    -538.7uA   -432.7uA   -651.9uA
-400mV    -425uA     -350.3uA   -505.9uA
6.6V      7.171mA    6.195mA    8.417mA
[Pullup]
|Voltage   I(typ)   I(min)   I(max)
-3.3V     4.509mA    3.165mA    5.44mA
-1.6V     4.328mA    3.165mA    5.44mA
4.2V      -10.62mA   -9.1mA     -13.68mA
4.8V      -12.8mA    -11mA      -15.6mA
5.1V      -13.6mA    -11mA      -16.8mA
5.2V      -13.8mA    -12mA      -17mA
5.7V      -16mA      -12mA      -18.3mA
5.9V      -16mA      -13mA      -19mA
6.2V      -16mA      -13mA      -20mA
6.3V      -16mA      -14mA      -20mA
6.5V      -17mA      -14mA      -21mA
6.6V      -17mA      -15mA      -21mA
[GND_clamp]
|Voltage   I(typ)   I(min)   I(max)
-3.3V     -9.429A    -9.432A    -9.905A
-1.2V     -2.113A    -2.844A    -1.842A
-1.13V    -1.502A    -2.228A    -1.224A
-1.06V    -927mA     -1.634A    -653.1mA
-990mV    -428.7mA   -1.078A    -200.2mA
-920mV    -105.4mA   -587.6mA   -23.28mA
-850mV    -14.68mA   -223.7mA   -6.667mA
-780mV    -4.207mA   -50.77mA   -4.248mA
-710mV    -2.321mA   -9.261mA   -2.639mA
-640mV    -1.305mA   -2.349mA   -1.385mA
3.28V     0A         0A         0A
[POWER_clamp]
|Voltage   I(typ)   I(min)   I(max)
-3.28V    0A         210.1nA    0A
-3.12V    0A         184.2nA    0A
-2.96V    0A         164.6nA    0A
-2.8V     0A         150.7nA    0A
-2.6V     0A         139nA      0A
-2.16V    0A         123.2nA    0A
-240mV    0A         69.7nA     0A
-200mV    0A         67.32nA    0A
-160mV    0A         60.72nA    0A
-120mV    0A         52.23nA    0A
-80mV     0A         0A         0A
0V        0A         0A         0A
[Ramp]
| variable   typ   min   max
dV/dt_r  1.13460/1.45711n   0.84588/2.13060n   1.34694/1.13276n
dV/dt_f  0.69918/2.39455n   0.51894/4.42738n   0.84306/1.97669n
R_load = 0.500000k
[Rising Waveform]
R_fixture= 0.500000k
V_fixture= 3.300000
V_fixture_min= 2.700000
V_fixture_max= 3.600000
|time   V(typ)   V(min)   V(max)
0s        2.135V     1.835V     2.195V
1.376ns   2.133V     1.835V     2.198V
2.127ns   2.159V     1.835V     2.636V
2.628ns   2.301V     1.835V     3.175V
3.003ns   2.528V     1.839V     3.405V
3.754ns   3.037V     1.89V      3.567V
4.254ns   3.199V     1.964V     3.588V
6.256ns   3.296V     2.603V     3.599V
7.758ns   3.299V     2.69V      3.599V
62.31ns   3.3V       2.7V       3.6V
[Rising Waveform]
R_fixture= 0.500000k
V_fixture= 0.0
V_fixture_min= 0.0
V_fixture_max= 0.0
|time   V(typ)   V(min)   V(max)
0s        16.21uV    12.7uV     8.632uV
1.752ns   -603.1uV   -56.5uV    105.5mV
2.503ns   62.23mV    -1.115mV   882.9mV
3.003ns   264.6mV    403.2uV    1.538V
3.504ns   677.4mV    6.378mV    1.9V
4.379ns   1.407V     69.97mV    2.143V
5.506ns   1.757V     374.3mV    2.222V
7.382ns   1.873V     1.121V     2.24V
10.14ns   1.889V     1.381V     2.244V
62.31ns   1.891V     1.41V      2.245V
[Falling Waveform]
R_fixture= 0.500000k
V_fixture= 3.300000
V_fixture_min= 2.700000
V_fixture_max= 3.600000
|time   V(typ)   V(min)   V(max)
0s        3.3V       2.7V       3.6V
1.126ns   3.303V     2.702V     3.588V
1.752ns   3.282V     2.702V     3.227V
3.003ns   2.817V     2.686V     2.714V
4.004ns   2.542V     2.494V     2.35V
5.255ns   2.249V     2.289V     2.242V
5.881ns   2.193V     2.222V     2.219V
9.51ns    2.144V     1.907V     2.196V
13.01ns   2.139V     1.839V     2.195V
62.31ns   2.135V     1.835V     2.195V
[Falling Waveform]
R_fixture= 0.500000k
V_fixture= 0.0
V_fixture_min= 0.0
V_fixture_max= 0.0
|time   V(typ)   V(min)   V(max)
0s        1.891V     1.41V      2.245V
1.502ns   1.877V     1.404V     2.089V
2.753ns   1.543V     1.371V     1.393V
3.629ns   1.138V     1.249V     667.7mV
4.254ns   780.9mV    1.096V     359.6mV
5.13ns    379.3mV    831.5mV    156.5mV
6.507ns   129.4mV    416.1mV    41.23mV
8.133ns   42.27mV    137mV      12.11mV
12.51ns   -105.8uV   5.282mV    125.5uV
62.31ns   16.21uV    12.7uV     8.632uV
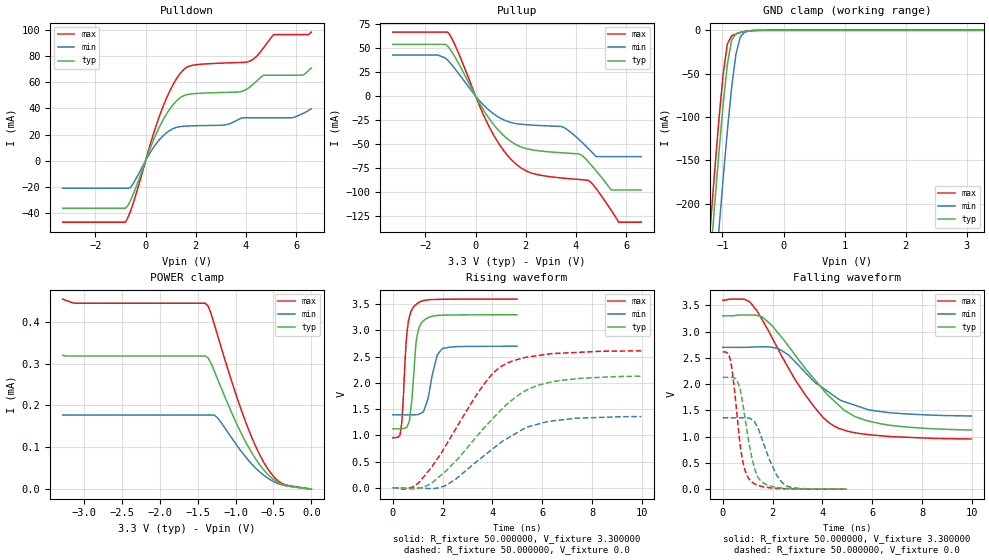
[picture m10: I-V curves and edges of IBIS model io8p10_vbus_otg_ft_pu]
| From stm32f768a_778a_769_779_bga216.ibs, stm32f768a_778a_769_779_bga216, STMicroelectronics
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|   Model io8p10_vbus_otg_ft_pu
[Model]  io8p10_vbus_otg_ft_pu
Model_type I/O
Polarity   Non-Inverting
Enable   Active-Low
Vinl =   0.990000V
Vinh =   2.310000V
Vmeas =  1.650000V
Cref =   40.000000pF
Rref =   100.000000M
Vref =   0.0V
C_comp   3.304800pF   3.199300pF   3.429300pF
[Temperature Range]   25.000000   0.125000k   -40.000000
[Pullup Reference]   3.300000V   2.700000V   3.600000V
[Pulldown Reference]   0.0V   0.0V   0.0V
[POWER Clamp Reference]   3.300000V   2.700000V   3.600000V
[GND Clamp Reference]   0.0V   0.0V   0.0V
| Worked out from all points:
|   slope of the pulldown table from 0 to 0.495 V, typ, clamps not added: 20.9 ohm
|   slope of the pullup table from 0 to 0.495 V, typ, clamps not added: 22.6 ohm
|   GND clamp passes 1 mA (typ) near -0.61 V on its own axis
|   rising waveform, R_fixture 50.000000, V_fixture 3.300000: 20-80 % time 227ps typ, 353ps min, 205ps max; typ from 1.12 V to 3.3 V
|   rising waveform, R_fixture 50.000000, V_fixture 0.0: 20-80 % time 2.51ns typ, 2.32ns min, 2.1ns max; typ from 0.001 V to 2.13 V
|   falling waveform, R_fixture 50.000000, V_fixture 3.300000: 20-80 % time 2.34ns typ, 2.08ns min, 2.05ns max; typ from 3.3 V to 1.12 V
|   falling waveform, R_fixture 50.000000, V_fixture 0.0: 20-80 % time 481ps typ, 678ps min, 388ps max; typ from 2.13 V to 0.001 V
[Pulldown]
|Voltage   I(typ)   I(min)   I(max)
-3.3V     -36.41mA   -21.08mA   -47.04mA
-800mV    -36.41mA   -21.08mA   -47.04mA
-600mV    -30.48mA   -20.53mA   -38.65mA
700mV     31.4mA     19.11mA    41.71mA
1.2V      45.15mA    25.37mA    61.75mA
1.6V      50.35mA    26.5mA     71.06mA
3.1V      52.28mA    27.26mA    74.76mA
4.1V      55.64mA    32.87mA    75.8mA
4.7V      65.47mA    32.87mA    86.49mA
5.1V      65.47mA    32.87mA    96.56mA
6.2V      65.47mA    35.57mA    96.56mA
6.6V      70.92mA    39.71mA    98.46mA
[Pullup]
|Voltage   I(typ)   I(min)   I(max)
-3.3V     54.06mA    42.89mA    66.91mA
-1.1V     51.85mA    37.21mA    66.69mA
500mV     -22.06mA   -14mA      -30.03mA
1.5V      -49.1mA    -28.3mA    -68.56mA
2.2V      -56.04mA   -30.32mA   -80.35mA
3.5V      -59.52mA   -32.65mA   -85.91mA
4.2V      -61.44mA   -47.48mA   -87.46mA
4.5V      -69.06mA   -55.12mA   -88.39mA
4.8V      -78.22mA   -63.4mA    -96.84mA
5.4V      -98.3mA    -63.4mA    -119.6mA
5.7V      -98.3mA    -63.4mA    -132mA
6.6V      -98.3mA    -63.4mA    -132mA
[GND_clamp]
|Voltage   I(typ)   I(min)   I(max)
-3.3V     -2.321A    -2.399A    -2.294A
-1.2V     -265.6mA   -356.2mA   -227.3mA
-1.13V    -202.8mA   -293mA     -164.3mA
-1.06V    -142.3mA   -231.2mA   -104.3mA
-990mV    -86.15mA   -171.7mA   -51mA
-920mV    -39.05mA   -115.6mA   -15.71mA
-850mV    -11.4mA    -65.74mA   -6.366mA
-780mV    -4.046mA   -27.6mA    -4.153mA
-710mV    -2.285mA   -7.882mA   -2.591mA
-640mV    -1.291mA   -2.274mA   -1.367mA
-570mV    -618uA     -909.9uA   -567.3uA
3.28V     0A         0A         0A
[POWER_clamp]
|Voltage   I(typ)   I(min)   I(max)
-3.28V    319.9uA    177.1uA    454.3uA
-3.12V    318.3uA    177.1uA    444.3uA
-1.4V     318.3uA    177.1uA    444.3uA
-1.36V    313.4uA    177.1uA    437.2uA
-1.28V    282.3uA    177.1uA    394.1uA
-1.24V    264.6uA    170.9uA    369.7uA
-920mV    131.9uA    89.38uA    187.2uA
-760mV    79.47uA    55.16uA    112.7uA
-640mV    48.78uA    35.06uA    68.06uA
-520mV    26.21uA    20.13uA    35uA
-400mV    12.52uA    10.84uA    14.88uA
0V        0A         0A         0A
[Ramp]
| variable   typ   min   max
dV/dt_r  1.26709/2.50565n   0.81135/2.32683n   1.56460/2.10544n
dV/dt_f  1.28208/2.32143n   0.77472/2.05782n   1.57422/2.04765n
R_load = 50.000000
[Rising Waveform]
R_fixture= 50.000000
V_fixture= 3.300000
V_fixture_min= 2.700000
V_fixture_max= 3.600000
|time   V(typ)   V(min)   V(max)
0s        1.125V     1.393V     955.6mV
300.3ps   1.127V     1.393V     1.026V
370.4ps   1.129V     1.393V     1.283V
580.6ps   1.174V     1.393V     2.996V
670.7ps   1.283V     1.393V     3.264V
850.9ps   2.214V     1.394V     3.455V
940.9ps   2.777V     1.395V     3.498V
1.111ns   3.111V     1.419V     3.551V
1.982ns   3.291V     2.653V     3.595V
4.985ns   3.3V       2.7V       3.599V
[Rising Waveform]
R_fixture= 50.000000
V_fixture= 0.0
V_fixture_min= 0.0
V_fixture_max= 0.0
|time   V(typ)   V(min)   V(max)
0s        1.432mV    1.238mV    1.804mV
460.5ps   -1.342mV   1.179mV    -23.95mV
1.041ns   -6.428mV   -821.5uV   95.7mV
1.542ns   81.44mV    -14.79mV   384.2mV
2.142ns   326.3mV    50.72mV    818mV
3.624ns   1.122V     598mV      1.952V
4.444ns   1.534V     902.1mV    2.341V
5.225ns   1.828V     1.118V     2.476V
6.186ns   2V         1.261V     2.547V
9.97ns    2.129V     1.359V     2.612V
[Falling Waveform]
R_fixture= 50.000000
V_fixture= 3.300000
V_fixture_min= 2.700000
V_fixture_max= 3.600000
|time   V(typ)   V(min)   V(max)
0s        3.3V       2.7V       3.599V
1.081ns   3.315V     2.702V     3.566V
1.602ns   3.272V     2.711V     3.208V
2.242ns   2.96V      2.675V     2.647V
3.303ns   2.302V     2.227V     1.798V
4.004ns   1.908V     1.93V      1.377V
4.484ns   1.674V     1.77V      1.198V
5.305ns   1.383V     1.598V     1.075V
6.326ns   1.247V     1.478V     1.018V
9.97ns    1.125V     1.393V     955.6mV
[Falling Waveform]
R_fixture= 50.000000
V_fixture= 0.0
V_fixture_min= 0.0
V_fixture_max= 0.0
|time   V(typ)   V(min)   V(max)
0s        2.129V     1.359V     2.612V
300.3ps   2.13V      1.359V     2.479V
460.5ps   2.118V     1.359V     1.943V
620.6ps   2.02V      1.359V     1.191V
850.9ps   1.491V     1.361V     432.3mV
1.111ns   737mV      1.344V     164.4mV
1.491ns   178.2mV    1.071V     63.45mV
2.142ns   37.27mV    285.1mV    15.82mV
2.452ns   19.1mV     99.6mV     10.86mV
4.985ns   1.432mV    1.238mV    1.804mV
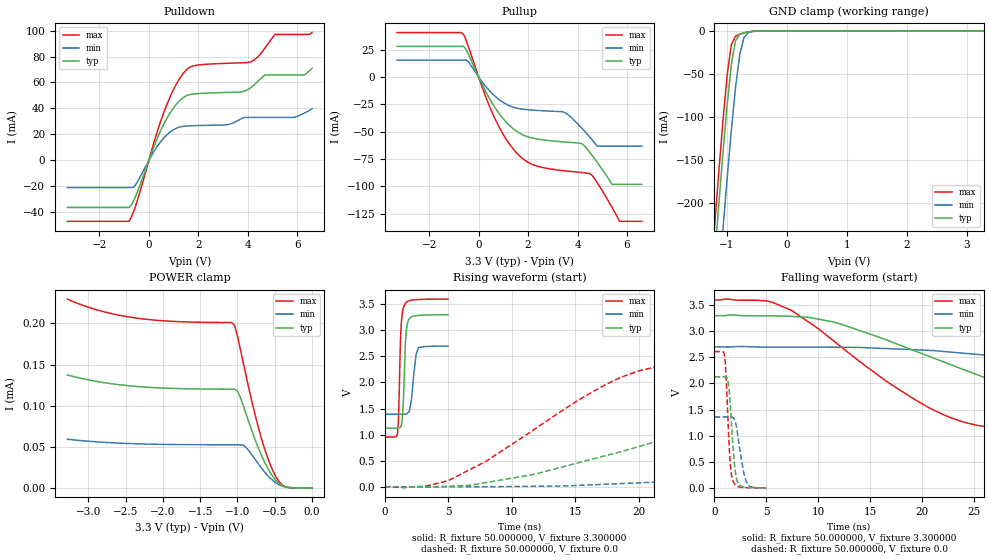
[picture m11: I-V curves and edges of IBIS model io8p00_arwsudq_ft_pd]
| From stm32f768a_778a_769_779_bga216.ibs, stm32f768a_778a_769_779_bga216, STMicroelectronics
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|   Model io8p00_arwsudq_ft_pd
[Model]  io8p00_arwsudq_ft_pd
Model_type I/O
Polarity   Non-Inverting
Enable   Active-Low
Vinl =   0.990000V
Vinh =   2.310000V
Vmeas =  1.650000V
Cref =   50.000000pF
Rref =   100.000000M
Vref =   0.0V
C_comp   2.905500pF   2.831700pF   2.987900pF
[Temperature Range]   25.000000   0.125000k   -40.000000
[Pullup Reference]   3.300000V   2.700000V   3.600000V
[Pulldown Reference]   0.0V   0.0V   0.0V
[POWER Clamp Reference]   3.300000V   2.700000V   3.600000V
[GND Clamp Reference]   0.0V   0.0V   0.0V
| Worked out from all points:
|   slope of the pulldown table from 0 to 0.495 V, typ, clamps not added: 20.9 ohm
|   slope of the pullup table from 0 to 0.495 V, typ, clamps not added: 22.6 ohm
|   GND clamp passes 1 mA (typ) near -0.62 V on its own axis
|   rising waveform, R_fixture 50.000000, V_fixture 3.300000: 20-80 % time 211ps typ, 337ps min, 188ps max; typ from 1.12 V to 3.3 V
|   rising waveform, R_fixture 50.000000, V_fixture 0.0: 20-80 % time 19.7ns typ, 50.8ns min, 10.3ns max; typ from 0 V to 2.13 V
|   falling waveform, R_fixture 50.000000, V_fixture 3.300000: 20-80 % time 18.5ns typ, 38.3ns min, 11.4ns max; typ from 3.3 V to 1.12 V
|   falling waveform, R_fixture 50.000000, V_fixture 0.0: 20-80 % time 460ps typ, 653ps min, 371ps max; typ from 2.13 V to 0 V
[Pulldown]
|Voltage   I(typ)   I(min)   I(max)
-3.3V     -36.4mA    -21.07mA   -47.09mA
-800mV    -36.4mA    -21.07mA   -47.09mA
-600mV    -30.5mA    -20.54mA   -38.69mA
700mV     31.4mA     19.11mA    41.71mA
1.2V      45.15mA    25.37mA    61.75mA
1.6V      50.35mA    26.5mA     71.06mA
3.1V      52.27mA    27.26mA    74.75mA
4.1V      55.71mA    33.04mA    75.8mA
4.7V      65.8mA     33.04mA    86.69mA
5.1V      65.8mA     33.04mA    97.03mA
6.3V      65.87mA    36.5mA     97.03mA
6.6V      70.92mA    39.71mA    98.48mA
[Pullup]
|Voltage   I(typ)   I(min)   I(max)
-3.3V     28.03mA    15.43mA    40.67mA
-700mV    28.03mA    15.43mA    40.67mA
-400mV    20.31mA    13.47mA    26.93mA
600mV     -25.77mA   -16.23mA   -35.13mA
1.6V      -50.64mA   -28.81mA   -70.96mA
3.5V      -59.53mA   -32.65mA   -85.92mA
4.2V      -61.44mA   -47.49mA   -87.46mA
4.5V      -69.08mA   -55.13mA   -88.39mA
4.8V      -78.24mA   -63.4mA    -96.88mA
5.4V      -98.3mA    -63.4mA    -119.6mA
5.7V      -98.3mA    -63.4mA    -132.1mA
6.6V      -98.3mA    -63.4mA    -132.1mA
[GND_clamp]
|Voltage   I(typ)   I(min)   I(max)
-3.3V     -2.319A    -2.397A    -2.292A
-1.2V     -266mA     -356.3mA   -228.4mA
-1.13V    -203.2mA   -293mA     -165.3mA
-1.06V    -142.7mA   -231.3mA   -105.2mA
-990mV    -86.51mA   -171.7mA   -51.78mA
-920mV    -39.3mA    -115.7mA   -15.95mA
-850mV    -11.38mA   -65.76mA   -6.112mA
-780mV    -3.842mA   -27.55mA   -3.895mA
-710mV    -2.102mA   -7.755mA   -2.396mA
-640mV    -1.159mA   -2.138mA   -1.234mA
-570mV    -535.1uA   -809uA     -490.4uA
3.28V     81.28uA    57.87uA    93.98uA
[POWER_clamp]
|Voltage   I(typ)   I(min)   I(max)
-3.28V    137.3uA    59.14uA    229.6uA
-2.36V    123.4uA    53.65uA    206.6uA
-1.08V    120.1uA    52.41uA    201.1uA
-1.04V    120uA      52.41uA    198uA
-1V       117.7uA    52.4uA     184.5uA
-920mV    99.46uA    51.91uA    151.2uA
-720mV    48.42uA    29.12uA    73.51uA
-600mV    24.82uA    15.47uA    37.72uA
-520mV    13.1uA     8.45uA     19.84uA
-440mV    5.058uA    3.61uA     7.276uA
-360mV    1.193uA    1.129uA    1.311uA
0V        0A         0A         0A
[Ramp]
| variable   typ   min   max
dV/dt_r  1.27668/19.71514n   0.81534/50.90980n   1.56653/10.33467n
dV/dt_f  1.30596/18.44728n   0.78492/38.38382n   1.58741/11.33419n
R_load = 50.000000
[Rising Waveform]
R_fixture= 50.000000
V_fixture= 3.300000
V_fixture_min= 2.700000
V_fixture_max= 3.600000
|time   V(typ)   V(min)   V(max)
0s        1.123V     1.39V      953.1mV
1.001ns   1.125V     1.391V     1.011V
1.071ns   1.127V     1.391V     1.26V
1.271ns   1.158V     1.391V     3.006V
1.371ns   1.269V     1.39V      3.314V
1.532ns   2.086V     1.39V      3.477V
1.672ns   2.92V      1.393V     3.532V
1.932ns   3.22V      1.444V     3.568V
2.653ns   3.286V     2.666V     3.591V
4.985ns   3.299V     2.699V     3.599V
[Rising Waveform]
R_fixture= 50.000000
V_fixture= 0.0
V_fixture_min= 0.0
V_fixture_max= 0.0
|time   V(typ)   V(min)   V(max)
0s        1.506uV    360.2nV    16.56uV
5.005ns   8.625mV    -158.1uV   117.5mV
11.51ns   225.4mV    7.801mV    1.055V
19.02ns   699.7mV    64.5mV     2.137V
28.03ns   1.328V     173.5mV    2.496V
36.54ns   1.789V     323.5mV    2.565V
46.55ns   1.99V      501.5mV    2.593V
88.09ns   2.117V     1.13V      2.611V
115.1ns   2.126V     1.291V     2.611V
249.2ns   2.128V     1.358V     2.611V
[Falling Waveform]
R_fixture= 50.000000
V_fixture= 3.300000
V_fixture_min= 2.700000
V_fixture_max= 3.600000
|time   V(typ)   V(min)   V(max)
0s        3.299V     2.699V     3.599V
5.506ns   3.295V     2.697V     3.56V
11.51ns   3.175V     2.694V     2.81V
22.02ns   2.416V     2.614V     1.405V
31.53ns   1.724V     2.434V     1.073V
36.54ns   1.476V     2.313V     1.037V
46.05ns   1.28V      2.081V     998.9mV
65.57ns   1.177V     1.699V     967.2mV
86.09ns   1.147V     1.528V     956.1mV
249.2ns   1.123V     1.39V      953.1mV
[Falling Waveform]
R_fixture= 50.000000
V_fixture= 0.0
V_fixture_min= 0.0
V_fixture_max= 0.0
|time   V(typ)   V(min)   V(max)
0s        2.128V     1.358V     2.611V
981ps     2.129V     1.357V     2.512V
1.151ns   2.12V      1.357V     1.99V
1.411ns   1.885V     1.358V     800mV
1.572ns   1.435V     1.359V     346.8mV
1.792ns   766.5mV    1.351V     127.9mV
2.182ns   137.4mV    1.093V     30.64mV
2.843ns   14.15mV    269.1mV    5.156mV
3.143ns   6.528mV    87.66mV    3.599mV
4.985ns   1.506uV    360.2nV    16.56uV
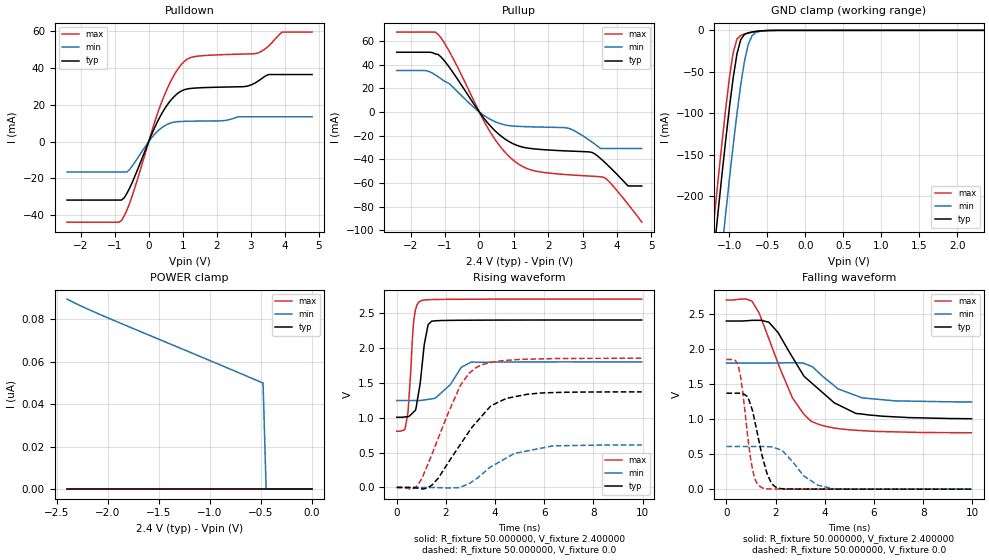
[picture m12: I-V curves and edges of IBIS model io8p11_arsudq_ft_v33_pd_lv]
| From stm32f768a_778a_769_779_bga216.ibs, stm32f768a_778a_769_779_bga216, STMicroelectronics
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|   Model io8p11_arsudq_ft_v33_pd_lv
[Model]  io8p11_arsudq_ft_v33_pd_lv
Model_type I/O
Polarity   Non-Inverting
Enable   Active-Low
Vinl =   0.720000V
Vinh =   1.680000V
Vmeas =  1.200000V
Cref =   30.000000pF
Rref =   100.000000M
Vref =   0.0V
C_comp   2.238700pF   2.180600pF   2.332300pF
[Temperature Range]   25.000000   0.125000k   -40.000000
[Pullup Reference]   2.400000V   1.800000V   2.700000V
[Pulldown Reference]   0.0V   0.0V   0.0V
[POWER Clamp Reference]   2.400000V   1.800000V   2.700000V
[GND Clamp Reference]   0.0V   0.0V   0.0V
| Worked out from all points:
|   slope of the pulldown table from 0 to 0.36 V, typ, clamps not added: 25 ohm
|   slope of the pullup table from 0 to 0.36 V, typ, clamps not added: 27.7 ohm
|   GND clamp passes 1 mA (typ) near -0.62 V on its own axis
|   rising waveform, R_fixture 50.000000, V_fixture 2.400000: 20-80 % time 304ps typ, 753ps min, 197ps max; typ from 1 V to 2.4 V
|   rising waveform, R_fixture 50.000000, V_fixture 0.0: 20-80 % time 1.7ns typ, 1.56ns min, 1.32ns max; typ from 0 V to 1.37 V
|   falling waveform, R_fixture 50.000000, V_fixture 2.400000: 20-80 % time 1.93ns typ, 1.44ns min, 1.38ns max; typ from 2.4 V to 1 V
|   falling waveform, R_fixture 50.000000, V_fixture 0.0: 20-80 % time 534ps typ, 996ps min, 389ps max; typ from 1.37 V to 0 V
[Pulldown]
|Voltage   I(typ)   I(min)   I(max)
-2.4V     -31.73mA   -16.51mA   -43.74mA
-800mV    -31.73mA   -16.51mA   -42.87mA
-480mV    -21.98mA   -13.17mA   -29.2mA
80mV      3.63mA     1.966mA    5.014mA
480mV     18.15mA    8.738mA    26.02mA
800mV     25.38mA    10.72mA    37.77mA
1.12V     28.53mA    11.02mA    44.6mA
2.8V      29.84mA    13.47mA    47.53mA
3.2V      32.64mA    13.47mA    48.04mA
3.52V     36.39mA    13.47mA    51.82mA
3.92V     36.39mA    13.47mA    59.43mA
4.8V      36.39mA    13.47mA    59.43mA
[Pullup]
|Voltage   I(typ)   I(min)   I(max)
-2.4V     50.45mA    35.08mA    67.47mA
-1.52V    50.45mA    34.74mA    67.47mA
-1.2V     48.6mA     29.87mA    65.62mA
-800mV    34.81mA    21.93mA    47.29mA
320mV     -11.75mA   -6.207mA   -17.08mA
1.04V     -27.53mA   -11.97mA   -41.91mA
1.6V      -31.13mA   -12.58mA   -49.63mA
2.56V     -32.88mA   -13.48mA   -52.9mA
3.28V     -34.19mA   -25.5mA    -54.18mA
3.6V      -41.31mA   -30.74mA   -54.97mA
4.32V     -62.42mA   -30.74mA   -77.81mA
4.72V     -62.42mA   -30.74mA   -93mA
[GND_clamp]
|Voltage   I(typ)   I(min)   I(max)
-2.4V     -1.424A    -1.508A    -1.393A
-1.25V    -311.2mA   -401.9mA   -273.3mA
-1.2V     -265.4mA   -356.1mA   -227.2mA
-1.15V    -220.4mA   -310.8mA   -181.9mA
-1.1V     -176.3mA   -266.2mA   -137.9mA
-1.05V    -133.8mA   -222.5mA   -95.87mA
-950mV    -57.3mA    -138.9mA   -26.99mA
-900mV    -28.28mA   -100.4mA   -10.6mA
-850mV    -11.02mA   -65.54mA   -5.972mA
-750mV    -2.846mA   -16.51mA   -3.192mA
-600mV    -761.3uA   -1.173mA   -751.9uA
2.35V     58.09uA    37.92uA    67.25uA
[POWER_clamp]
|Voltage   I(typ)   I(min)   I(max)
-2.4V     0A         89.62nA    0A
-2.04V    0A         81.57nA    0A
-480mV    0A         50.01nA    0A
-450mV    0A         0A         0A
0V        0A         0A         0A
[Ramp]
| variable   typ   min   max
dV/dt_r  0.82128/1.69522n   0.36854/1.63018n   1.11144/1.31717n
dV/dt_f  0.83394/1.93087n   0.33234/1.44059n   1.13586/1.38322n
R_load = 50.000000
[Rising Waveform]
R_fixture= 50.000000
V_fixture= 2.400000
V_fixture_min= 1.800000
V_fixture_max= 2.700000
|time   V(typ)   V(min)   V(max)
0s        1.005V     1.245V     804.5mV
320.3ps   1.01V      1.245V     826mV
440.4ps   1.015V     1.245V     1.038V
700.7ps   1.086V     1.245V     2.41V
961ps     1.511V     1.245V     2.67V
1.121ns   2.05V      1.254V     2.686V
1.281ns   2.335V     1.262V     2.69V
1.421ns   2.382V     1.269V     2.691V
3.043ns   2.396V     1.796V     2.697V
9.97ns    2.399V     1.799V     2.699V
[Rising Waveform]
R_fixture= 50.000000
V_fixture= 0.0
V_fixture_min= 0.0
V_fixture_max= 0.0
|time   V(typ)   V(min)   V(max)
0s        75.83uV    35.19uV    229.9uV
620.6ps   -2.456mV   18.55uV    -24.8mV
860.9ps   -11.41mV   62.1uV     36.44mV
1.441ns   35.94mV    -774.4uV   483mV
2.583ns   612.8mV    3.807mV    1.458V
3.243ns   934.9mV    125.6mV    1.72V
3.844ns   1.172V     299.2mV    1.792V
5.265ns   1.332V     520.1mV    1.837V
6.366ns   1.359V     596mV      1.846V
9.97ns    1.369V     608.5mV    1.85V
[Falling Waveform]
R_fixture= 50.000000
V_fixture= 2.400000
V_fixture_min= 1.800000
V_fixture_max= 2.700000
|time   V(typ)   V(min)   V(max)
0s        2.399V     1.799V     2.699V
1.041ns   2.408V     1.799V     2.683V
1.321ns   2.409V     1.799V     2.519V
1.722ns   2.383V     1.799V     2.15V
2.102ns   2.233V     1.801V     1.793V
2.683ns   1.884V     1.804V     1.304V
3.423ns   1.528V     1.757V     974.3mV
4.545ns   1.205V     1.43V      864.4mV
5.265ns   1.08V      1.336V     840.2mV
9.97ns    1.005V     1.245V     804.5mV
[Falling Waveform]
R_fixture= 50.000000
V_fixture= 0.0
V_fixture_min= 0.0
V_fixture_max= 0.0
|time   V(typ)   V(min)   V(max)
0s        1.369V     608.5mV    1.85V
460.5ps   1.37V      608.4mV    1.787V
660.7ps   1.365V     608.3mV    1.391V
1.001ns   1.183V     608.1mV    394.3mV
1.441ns   488.6mV    608.9mV    21.85mV
1.802ns   104.4mV    603.9mV    3.002mV
2.202ns   9.068mV    560.6mV    1.594mV
3.143ns   1.328mV    189.9mV    988.5uV
4.384ns   667.4uV    3.674mV    665.3uV
9.97ns    75.83uV    35.19uV    229.9uV
